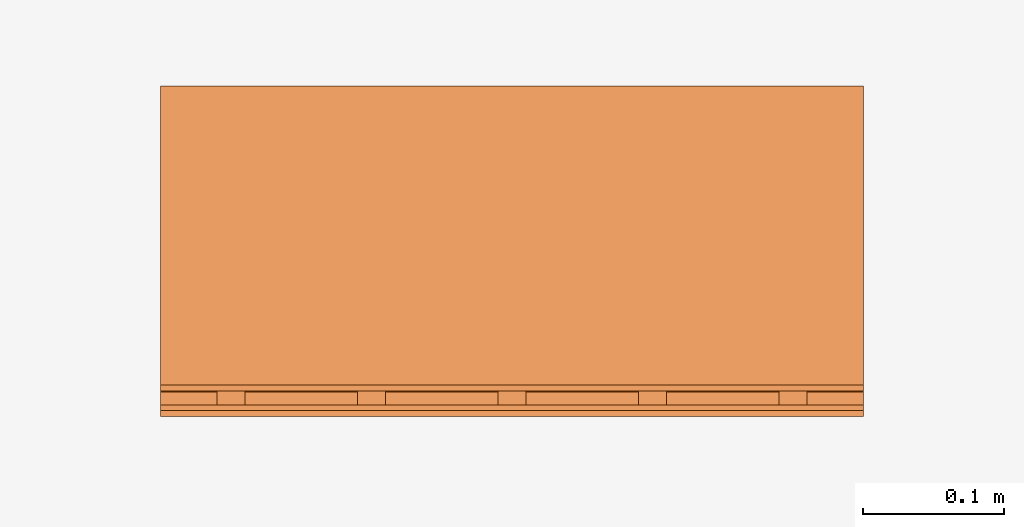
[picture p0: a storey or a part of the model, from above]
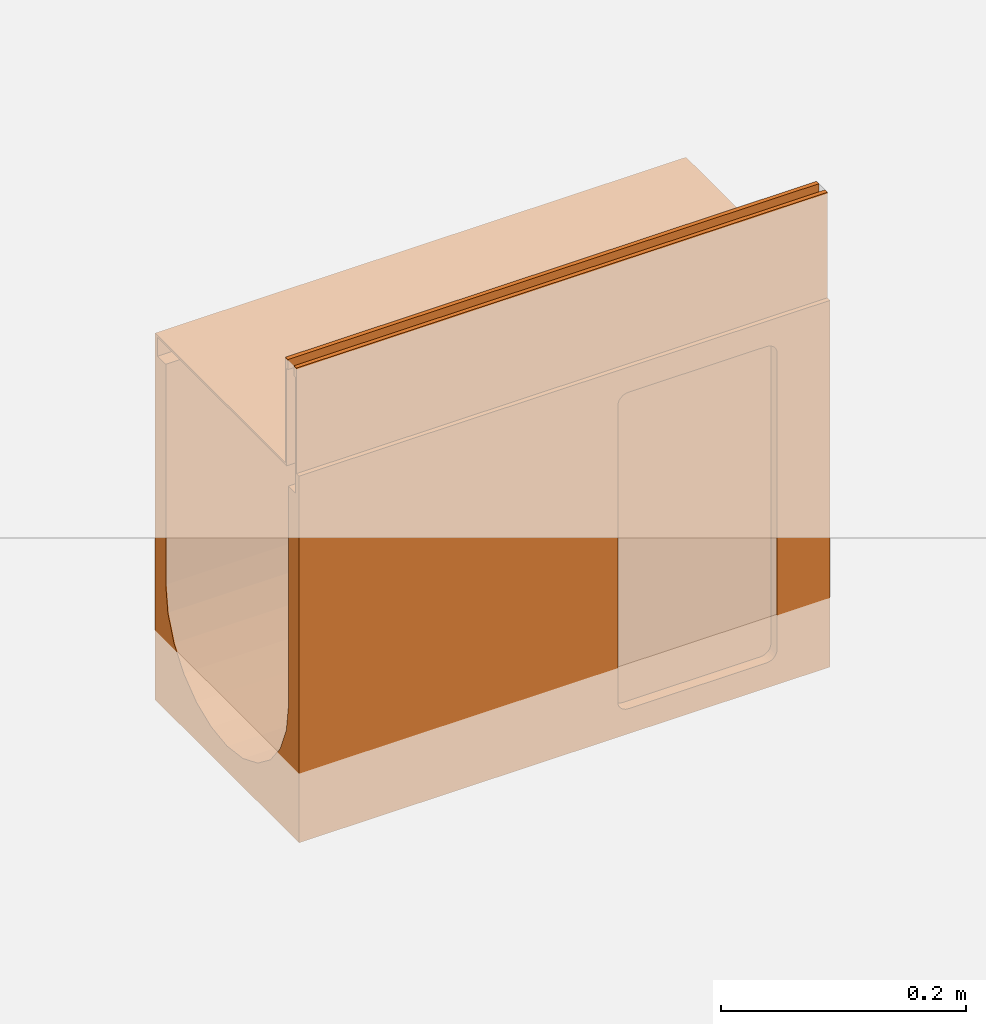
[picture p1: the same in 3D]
Properties of the parts of a building model (IFC2X3)

# File
Description: ViewDefinition [CoordinationView]
File name: 24215 - No 20.1 Constant Depth Channel - 500mm LG - Invert Depth 340mm.ifc
Time: 2013-10-30T14:06:44
Written by: Autodesk Revit 2013
Made in: 20120221_2030(x64)

# IfcProject, Project Number
LongName: Project Name; Phase: Project Status

# IfcSite, Default
RefLatitude: 42, 21, 30, 344238; RefLongitude: -71, -3, -35, -194702; RefElevation: 0 mm

# IfcBuilding
Pset_BuildingCommon - NumberOfStoreys: 1
Other - Project Issue Date: Issue Date; Project Address: ## Street City, State Zip; Project Status: Project Status; Project Name: Project Name; Project Number: Project Number; Client Name: Owner

# IfcBuildingStorey, Level 1
LongName: Level 1; Elevation: 0 mm
Constraints - Elevation Base: 0; Elevation: 0 mm
Graphics - Symbol at End 2 Default: yes; Symbol at End 1 Default: no; Color: 0; Line Pattern: Center; Symbol: M_Level Head - Circle: M_Level Head - Circle; Line Weight: 1
Identity Data - Name: Level 1; Structural: no; Building Story: yes
Dimensions - Computation Height: 0 mm

# IfcBuildingElementProxy: 24215 - No 20.1 Constant Depth Channel - 500mm LG - Invert Depth 340mm, Civil-Drainage-Channel-ACO-MultiDrain-M200DS-Brickslot-Channel-System:24215 - No 20.1 Constant Depth Channel - 500mm LG - Invert Depth 340mm:24215 - No 20.1 Constant Depth Channel - 500mm LG - Invert Depth 340mm:196059
In: Level 1
Material: Stainless Steel (F), Vienite® Synthetic Resin Concrete
Phasing - Phase Created: New Construction
Dimensions - Brickslot Access Unit Void Bottom Depth: 6105 mm; EndCap Position: 500 mm; Volume: 10233837 mm3; FloorCut_Length: -500 mm; Brickslot Void Length: -500 mm; Brickslot Grating Void Depth: 0 mm; Brickslot Access Unit Void Depth: 6000 mm; Length: 1000 mm; Custom_Void_Length: 0 mm; InvDepth: 240 mm; Depth: 365 mm; EndCap_Height: 365 mm; FloorCut_HorPosition: 117.5 mm; Length Drain: -500 mm; FloorCut_Depth: 365 mm; FloorCut_Width: 235 mm
Construction - 408999_Load Class C250 & D400_Brickslot Grating_Stainless Steel_500mm Long: yes; 409000_Load Class C250 & D400_Brickslot_Access Unit_Stainless Steel_500mm Long: no; 23219 - Universal Endcap (Male End): no; 23219 - Universal Endcap (Female End): no; 408998_Load Class C250 & D400_Brickslot Grating_Stainless Steel_1000mm Long: no; Shallow Depth Channel: no; Constant Depth Channel_500: yes; Shallow Depth Channel with seal: no; 23410_Sump Unit: no; Constant Depth Channel_1000: no
Constraints - Moves With Nearby Elements: no; Level: Level: Level 1
Pset_BuildingElementProxyCommon - Reference: 24215 - No 20.1 Constant Depth Channel - 500mm LG - Invert Depth 340mm
Data - Invert Depth: 340mm; Installation - Concrete Grade: Refer to brochure; Product Weight: 22.9 Kg; Concrete Surround Volume - Load Class D 400 - Concrete Pavement: 0.29m³/m; Concrete Surround Volume - Load Class A 15 - Concrete Pavement: 0.13m³/m; Hydraulic Performance: http://www.aco.co.uk/download.php?id=173; Product Standard: BS EN 1433:2002, CE marked; Concrete Surround Volume - Load Class B 125 - C 250 - Concrete Pavement: 0.20m³/m; Product Dimensions: 500mm x 235mm x 365mm (LxWxH); ACO Hydraulic Design Software: http://www.acodesign.co.uk; Load Class: A 15 - D 400; Channel C.S.A: 0.051m²
Identity Data - e-mail Sales: customersupport@aco.co.uk; Maintenance guidelines: http://www.aco.co.uk/download.php?id=173; Watermarked With: BIM Manager Premium Suite; Product brochure: http://www.aco.co.uk/download.php?id=173; URL: www.aco.co.uk; Manufacturer: ACO Technologies plc - ACO Water Management Division; Model: ACO MultiDrain MDS Brickslot - M200DS; e-mail Technical: technical@aco.co.uk; Assembly Description: Rain Water Drainage; Product Code: 24215; Product Page URL: http://www.aco.co.uk/product_detail.php?id=58; Watermark 2: This file is water marked and users are prohibited to reproduce, adapt, distribute this information; Watermark 1: This file is the property of ACO Technologies PLC; Address: ACO Business Park, Hitchin Road, Shefford, Bedfordshire, United Kingdom SG17 5TE; Model Description: Channel drainage system; Assembly Code: D2040; Watermarked By: www.aco.co.uk; OmniClass Number: 23.70.50.24; Telephone: +44 (0)1462 816666; Price: POA - contact ACO; OmniClass Title: Rainwater Removal; Type Comments: ACO MultiDrain M200DS 20.1J Constant Depth Channel 500mm Long; Installation guidelines: http://www.aco.co.uk/download.php?id=173; Fax: +44 (0)1462 815895; Cost: 0
Materials and Finishes - Edge Rail Colour: Self; Channel Colour: Brown; Edge Rail Material: Stainless Steel Grade 304; Channel Material: Vienite® Synthetic Resin Concrete
General - SerialNumber: 0; TagNumber: 0
Green Building Properties - Channel Recyclable: Fully recyclable; Channel Recycled Material Content: 20% minimum; Edge Rail Recycled Material Content: Between 40% - 90%; Edge Rail Recyclable: Fully recyclable
Model Properties - End Cap Product code 23219: No 306 Universal End Cap - 235mm wide x 365mm long - Spigot Ø160mm x 75mm long - Silver - Polypropylene - 0.4kg; Brickslot Grating Product code 408999: Load Class C250/D400 - Brickslot Stainless Steel - 500mm long x 105mm high - 10mm Slot - Intake area 10000mm²/m - 4.8kg; Brickslot Access Unit Product code 409000: Load Class C250/D400 - Brickslot Access Unit Stainless Steel - 500mm long x 105mm high - 10mm Slot - Intake area 10000mm²/m - 8.5 Kg; Brickslot Grating Product code 408998: N/A
Other - CreatedBy: www.aco.co.uk; Revision: 1

# IfcOpeningElement: Opening (2)
In: Level 1
Dimensions - Area: 24991000 mm2; Volume: 9964392500 mm3; Perimeter: 20000 mm; Thickness: 400 mm
Phasing - Phase Created: New Construction
Constraints - Related to Mass: no; Level: Level: Level 1; Height Offset From Level: 0 mm; Room Bounding: yes
Structural - Structural: no; Enable Analytical Model: no
Analytical Properties - Thermal mass: 543920; Absorptance: 0.1; Roughness: 1; Heat Transfer Coefficient (U): 2.0925; Thermal Resistance (R): 0.477897
Construction - Default Thickness: 400 mm; Function: 0
Materials and Finishes - Structural Material: Earth
Graphics - Coarse Scale Fill Color: 0

# IfcSlab: Floor:Generic Floor - 400mm, Floor:Generic Floor - 400mm:193825
In: Level 1
PredefinedType: FLOOR; Material: Earth 400 mm
Dimensions - Area: 24991000 mm2; Volume: 9964392500 mm3; Perimeter: 20000 mm; Thickness: 400 mm
Phasing - Phase Created: New Construction
Constraints - Related to Mass: no; Level: Level: Level 1; Height Offset From Level: 0 mm; Room Bounding: yes
Structural - Structural: no; Enable Analytical Model: no
Pset_SlabCommon - Reference: Generic Floor - 400mm; IsExternal: no; LoadBearing: yes
Analytical Properties - Thermal mass: 543920; Absorptance: 0.1; Roughness: 1; Heat Transfer Coefficient (U): 2.0925; Thermal Resistance (R): 0.477897
Construction - Default Thickness: 400 mm; Function: 0
Materials and Finishes - Structural Material: Earth
Graphics - Coarse Scale Fill Color: 0
